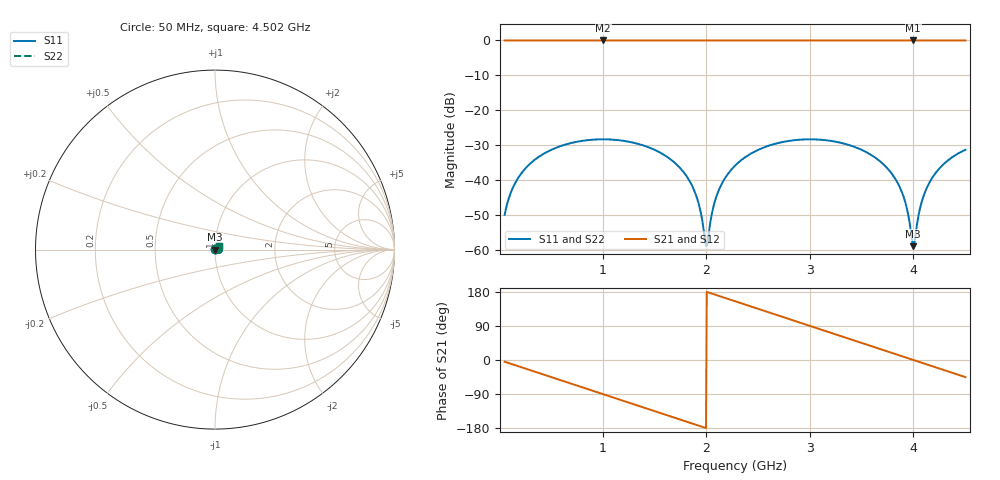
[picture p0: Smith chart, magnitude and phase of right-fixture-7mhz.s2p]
! Generated by 参数面去嵌台 (reference-plane de-embed bench)
# GHz S RI R 50
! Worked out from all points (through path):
!   637 points, 50 MHz to 4.502 GHz, reference 50 ohm
!   highest |S21| = -0.26 dB at 3.998 GHz (marker M1); lowest = -0.3 dB at 1.002 GHz (marker M2)
!   group delay of S21, straight-line fit = 250 ps
!   lowest |S11| = -58.8 dB at 3.998 GHz (marker M3), VSWR 1.00, Z = 50.1 - j0.0116 ohm
!   |S11| at or under -10 dB: start of sweep to end of sweep
!   |S22| runs from -58.8 to -28.4 dB; largest |S21 - S12| = 0
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0.05  0.00137 0.00289  0.9674 -0.0762  0.9674 -0.0762  0.00137 0.00289
0.148  0.0031 0.00828  0.9442 -0.2237  0.9442 -0.2237  0.0031 0.00828
0.295  0.00853 0.0148  0.8678 -0.4339  0.8678 -0.4339  0.00853 0.0148
0.792  0.0343 0.0112  0.311 -0.9186  0.311 -0.9186  0.0343 0.0112
1.002  0.0381 -0.000116  -0.00304 -0.9697  -0.00304 -0.9697  0.0381 -0.000116
1.261  0.0322 -0.0135  -0.3863 -0.8896  -0.3863 -0.8896  0.0322 -0.0135
1.534  0.0176 -0.0184  -0.7214 -0.6486  -0.7214 -0.6486  0.0176 -0.0184
1.842  0.00337 -0.0088  -0.9406 -0.2385  -0.9406 -0.2385  0.00337 -0.0088
1.919  0.00174 -0.00465  -0.9626 -0.1232  -0.9626 -0.1232  0.00174 -0.00465
1.996  0.00114 -0.000232  -0.9704 -0.0061  -0.9704 -0.0061  0.00114 -0.000232
2.115  0.00234 0.00653  -0.9546 0.1745  -0.9546 0.1745  0.00234 0.00653
2.276  0.00767 0.0141  -0.8804 0.4079  -0.8804 0.4079  0.00767 0.0141
2.668  0.0289 0.0159  -0.4829 0.8411  -0.4829 0.8411  0.0289 0.0159
3.018  0.038 -0.00104  0.0274 0.9693  0.0274 0.9693  0.038 -0.00104
3.452  0.0224 -0.0182  0.632 0.7359  0.632 0.7359  0.0224 -0.0182
3.76  0.00615 -0.0126  0.9021 0.3574  0.9021 0.3574  0.00615 -0.0126
3.9  0.00205 -0.00571  0.9584 0.1519  0.9584 0.1519  0.00205 -0.00571
3.998  0.00114 -0.000116  0.9704 0.00305  0.9704 0.00305  0.00114 -0.000116
4.082  0.00175 0.00471  0.9624 -0.1247  0.9624 -0.1247  0.00175 0.00471
4.166  0.0036 0.0092  0.9375 -0.2503  0.9375 -0.2503  0.0036 0.0092
4.306  0.00904 0.0151  0.8602 -0.4489  0.8602 -0.4489  0.00904 0.0151
4.502  0.0197 0.0185  0.6835 -0.6883  0.6835 -0.6883  0.0197 0.0185
